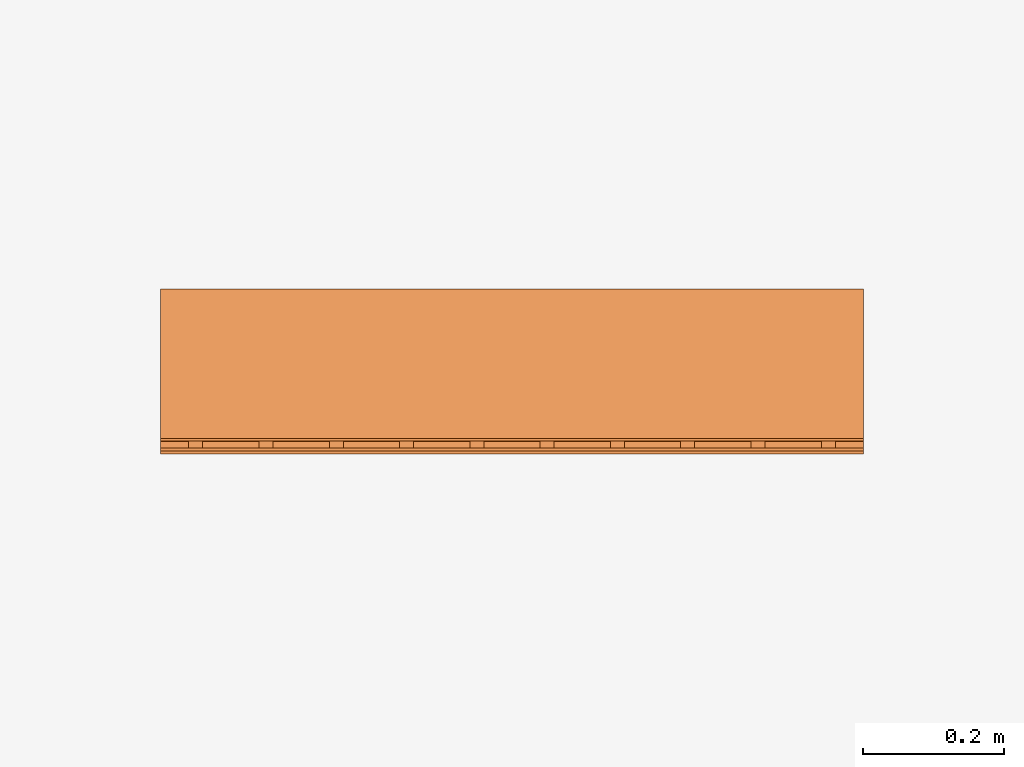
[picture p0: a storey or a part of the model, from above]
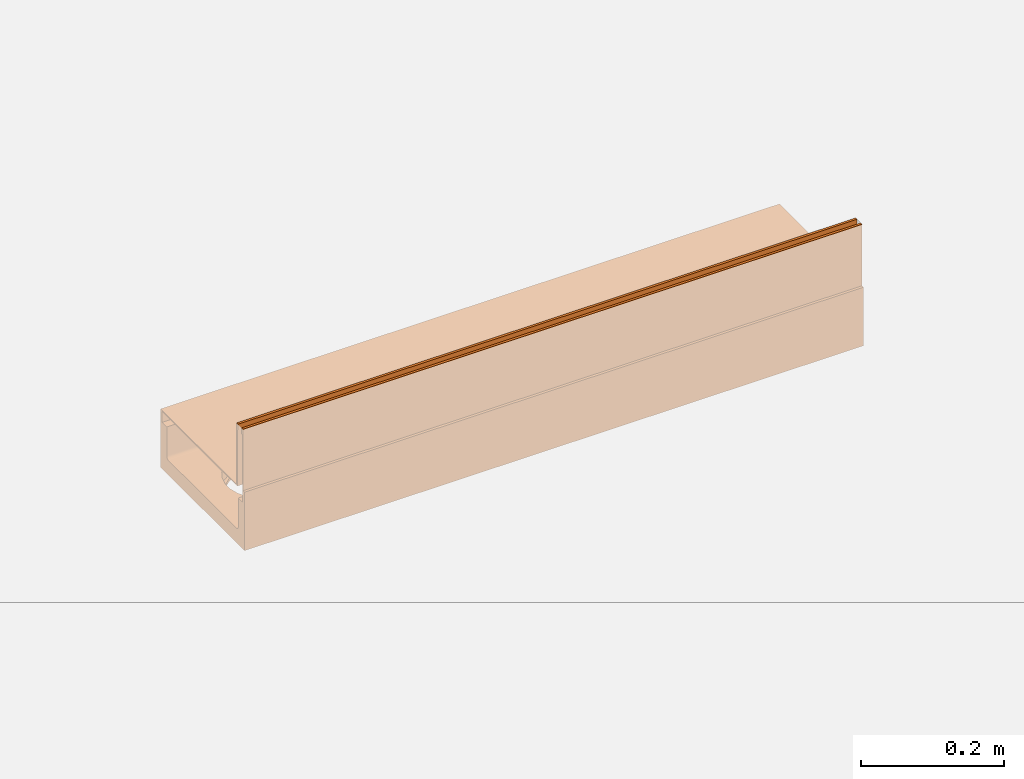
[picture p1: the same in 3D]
Properties of the parts of a building model (IFC2X3)

# File
Description: ViewDefinition [CoordinationView]
File name: 23217 - No 0100V Constant Depth Channel - 1000mm LG - Invert Depth 75mm.ifc
Time: 2013-10-30T13:49:25
Written by: Autodesk Revit 2013
Made in: 20120221_2030(x64)

# IfcProject, Project Number
LongName: Project Name; Phase: Project Status

# IfcSite, Default
RefLatitude: 42, 21, 30, 344238; RefLongitude: -71, -3, -35, -194702; RefElevation: 0 mm

# IfcBuilding
Pset_BuildingCommon - NumberOfStoreys: 1
Other - Project Address: ## Street City, State Zip; Project Name: Project Name; Client Name: Owner; Project Status: Project Status; Project Issue Date: Issue Date; Project Number: Project Number

# IfcBuildingStorey, Level 1
LongName: Level 1; Elevation: 0 mm
Constraints - Elevation Base: 0; Elevation: 0 mm
Graphics - Symbol at End 2 Default: yes; Line Weight: 1; Line Pattern: Center; Color: 0; Symbol: M_Level Head - Circle: M_Level Head - Circle; Symbol at End 1 Default: no
Dimensions - Computation Height: 0 mm
Identity Data - Building Story: yes; Name: Level 1; Structural: no

# IfcBuildingElementProxy: 23217 - No 0100V Constant Depth Channel - 1000mm LG - Invert Depth 75mm, Civil-Drainage-Channel-ACO-MultiDrain-M200D-Brickslot-Channel-System:23217 - No 0100V Constant Depth Channel - 1000mm LG - Invert Depth 75mm:23217 - No 0100V Constant Depth Channel - 1000mm LG - Invert Depth 75mm:196059
In: Level 1
Material: Steel, Galvanized, Plastic, Opaque Black, Vienite® Synthetic Resin Concrete
Model Properties - Brickslot Grating Product code 408996: Load Class C250/D400 - Brickslot Galvanized Steel - 500mm long x 105mm high - 10mm Slot - Intake area - 10000mm²/m - 4.8kg; End Cap Product code 23219: No. 306 Universal End Cap - 235mm wide x 365mm long - Spigot Ø160mm x 75mm long - Silver - Polypropylene - 0.4kg; Brickslot Grating Product code 408995: Load Class C250/D400 - Brickslot Galvanized Steel - 1000mm long x 105mm high - 10mm Slot - Intake area - 10000mm²/m - 9.8kg; Brickslot Access Unit Product code 408997: Load Class C250/D400 - Brickslot Access Unit Galvanised Steel - 500mm long x 105mm high - 10mm Slot - Intake area - 10000mm²/m 8.5 Kg
Dimensions - Brickslot Access Void Depth: -6000 mm; Brickslot Grating Void Depth: 0 mm; Brickslot Access Unit Void Bottom Depth: -6105 mm; EndCap Position: 1000 mm; Brickslot Void Length: -1000 mm; FloorCut_Length: -1000 mm; Custom_Void_Length: 0 mm; Volume: 8970757 mm3; Length: 1000 mm; InvDepth: 240 mm; Length Drain: -1000 mm; FloorCut_HorPosition: 117.5 mm; FloorCut_Width: 235 mm; EndCap_Height: 100 mm; FloorCut_Depth: 100 mm; Depth: 365 mm; Brickslot Access unit void length: -500 mm
Phasing - Phase Created: New Construction
Constraints - Level: Level: Level 1; Moves With Nearby Elements: no
Construction - 408995_Load Class C250 & D400_Brickslot Grating_Galvanized Steel_1000mm Long: yes; 23219 - Universal Endcap (Female End): no; 23219 - Universal Endcap (Male End): no; 408996_Load Class C250 & D400_Brickslot Grating_Galvanized Steel_500mm Long: no; 408997_Load Class C250 & D400_Brickslot_Access Unit_Galvanized Steel_500mm Long: no; Shallow Depth Channel: no; 23410_Sump Unit: no; Shallow Depth Channel with seal: yes; Constant Depth Channel_1000: no; Constant Depth Channel_500: no
Pset_BuildingElementProxyCommon - Reference: 23217 - No 0100V Constant Depth Channel - 1000mm LG - Invert Depth 75mm
Data - Invert Depth: 75mm; Concrete Surround Volume - Load Class A 15 - Concrete Pavement: 0.06m³/m; Concrete Surround Volume - Load Class D 400 - Concrete Pavement: 0.17m³/m; Pre-formed Outlet Ø: N/A; ACO Hydraulic Design Software: http://www.acodesign.co.uk; Installation - Concrete Grade: Refer to brochure; Hydraulic Performance: http://www.aco.co.uk/download.php?id=173; Product Weight: 17.0Kg; Product Dimensions: 1000mm x 235mm x 100mm (LxWxH); Load Class: A 15 - D 400; Channel C.S.A: 0.01m²; Concrete Surround Volume - Load Class B 125 - C 250 - Concrete Pavement: 0.11m³/m; Product Standard: BS EN 1433:2002, CE marked
Identity Data - Model Description: Channel drainage system; Maintenance guidelines: http://www.aco.co.uk/download.php?id=173; OmniClass Title: Rainwater Removal; Watermarked By: www.aco.co.uk; Installation guidelines: http://www.aco.co.uk/download.php?id=173; Product brochure: http://www.aco.co.uk/download.php?id=173; Cost: 0; Model: ACO MultiDrain MD Brickslot - M200D; OmniClass Number: 23.70.50.24; Watermark 2: This file is water marked and users are prohibited to reproduce, adapt, distribute this information; Product Page URL: http://www.aco.co.uk/product_detail.php?id=58; Telephone: +44 (0)1462 816666; Assembly Code: D2040; Fax: +44 (0)1462 815895; Type Comments: ACO MultiDrain M200D 0100V Shallow Constant Depth Channel 1000mm Long; Assembly Description: Rain Water Drainage; Product Code: 23217; Watermark 1: This file is the property of ACO Technologies PLC; Watermarked With: BIM Manager Premium Suite; e-mail Sales: customersupport@aco.co.uk; URL: www.aco.co.uk; e-mail Technical: technical@aco.co.uk; Address: ACO Business Park, Hitchin Road, Shefford, Bedfordshire, United Kingdom SG17 5TE; Price: POA - contact ACO; Manufacturer: ACO Technologies plc - ACO Water Management Division
General - SerialNumber: 0; TagNumber: 0
Materials and Finishes - Edge Rail Colour: Silver; Edge Rail Material: Steel; Channel Colour: Brown; Edge Rail Finish: Pre-galvanised; Channel Material: Vienite® Synthetic Resin Concrete
Green Building Properties - Channel Recyclable: Fully recyclable; Channel Recycled Material Content: 20% minimum; Edge Rail Recycled Material Content: Between 40% - 90%; Edge Rail Recyclable: Fully recyclable
Other - CreatedBy: www.aco.co.uk; Revision: 1

# IfcOpeningElement: Opening, Civil-Drainage-Channel-ACO-MultiDrain-M200D-Brickslot-Channel-System:23217 - No 0100V Constant Depth Channel - 1000mm LG - Invert Depth 75mm:23217 - No 0100V Constant Depth Channel - 1000mm LG - Invert Depth 75mm:196059:1
In: Level 1
Model Properties - Brickslot Grating Product code 408996: Load Class C250/D400 - Brickslot Galvanized Steel - 500mm long x 105mm high - 10mm Slot - Intake area - 10000mm²/m - 4.8kg; End Cap Product code 23219: No. 306 Universal End Cap - 235mm wide x 365mm long - Spigot Ø160mm x 75mm long - Silver - Polypropylene - 0.4kg; Brickslot Grating Product code 408995: Load Class C250/D400 - Brickslot Galvanized Steel - 1000mm long x 105mm high - 10mm Slot - Intake area - 10000mm²/m - 9.8kg; Brickslot Access Unit Product code 408997: Load Class C250/D400 - Brickslot Access Unit Galvanised Steel - 500mm long x 105mm high - 10mm Slot - Intake area - 10000mm²/m 8.5 Kg
Dimensions - Brickslot Access Void Depth: -6000 mm; Brickslot Grating Void Depth: 0 mm; Brickslot Access Unit Void Bottom Depth: -6105 mm; EndCap Position: 1000 mm; Brickslot Void Length: -1000 mm; FloorCut_Length: -1000 mm; Custom_Void_Length: 0 mm; Volume: 8970757 mm3; Length: 1000 mm; InvDepth: 240 mm; Length Drain: -1000 mm; FloorCut_HorPosition: 117.5 mm; FloorCut_Width: 235 mm; EndCap_Height: 100 mm; FloorCut_Depth: 100 mm; Depth: 365 mm; Brickslot Access unit void length: -500 mm
Phasing - Phase Created: New Construction
Constraints - Level: Level: Level 1; Moves With Nearby Elements: no
Construction - 408995_Load Class C250 & D400_Brickslot Grating_Galvanized Steel_1000mm Long: yes; 23219 - Universal Endcap (Female End): no; 23219 - Universal Endcap (Male End): no; 408996_Load Class C250 & D400_Brickslot Grating_Galvanized Steel_500mm Long: no; 408997_Load Class C250 & D400_Brickslot_Access Unit_Galvanized Steel_500mm Long: no; Shallow Depth Channel: no; 23410_Sump Unit: no; Shallow Depth Channel with seal: yes; Constant Depth Channel_1000: no; Constant Depth Channel_500: no
Data - Invert Depth: 75mm; Concrete Surround Volume - Load Class A 15 - Concrete Pavement: 0.06m³/m; Concrete Surround Volume - Load Class D 400 - Concrete Pavement: 0.17m³/m; Pre-formed Outlet Ø: N/A; ACO Hydraulic Design Software: http://www.acodesign.co.uk; Installation - Concrete Grade: Refer to brochure; Hydraulic Performance: http://www.aco.co.uk/download.php?id=173; Product Weight: 17.0Kg; Product Dimensions: 1000mm x 235mm x 100mm (LxWxH); Load Class: A 15 - D 400; Channel C.S.A: 0.01m²; Concrete Surround Volume - Load Class B 125 - C 250 - Concrete Pavement: 0.11m³/m; Product Standard: BS EN 1433:2002, CE marked
Identity Data - Model Description: Channel drainage system; Maintenance guidelines: http://www.aco.co.uk/download.php?id=173; OmniClass Title: Rainwater Removal; Watermarked By: www.aco.co.uk; Installation guidelines: http://www.aco.co.uk/download.php?id=173; Product brochure: http://www.aco.co.uk/download.php?id=173; Cost: 0; Model: ACO MultiDrain MD Brickslot - M200D; OmniClass Number: 23.70.50.24; Watermark 2: This file is water marked and users are prohibited to reproduce, adapt, distribute this information; Product Page URL: http://www.aco.co.uk/product_detail.php?id=58; Telephone: +44 (0)1462 816666; Assembly Code: D2040; Fax: +44 (0)1462 815895; Type Comments: ACO MultiDrain M200D 0100V Shallow Constant Depth Channel 1000mm Long; Assembly Description: Rain Water Drainage; Product Code: 23217; Watermark 1: This file is the property of ACO Technologies PLC; Watermarked With: BIM Manager Premium Suite; e-mail Sales: customersupport@aco.co.uk; URL: www.aco.co.uk; e-mail Technical: technical@aco.co.uk; Address: ACO Business Park, Hitchin Road, Shefford, Bedfordshire, United Kingdom SG17 5TE; Price: POA - contact ACO; Manufacturer: ACO Technologies plc - ACO Water Management Division
General - SerialNumber: 0; TagNumber: 0
Materials and Finishes - Edge Rail Colour: Silver; Edge Rail Material: Steel; Channel Colour: Brown; Edge Rail Finish: Pre-galvanised; Channel Material: Vienite® Synthetic Resin Concrete
Green Building Properties - Channel Recyclable: Fully recyclable; Channel Recycled Material Content: 20% minimum; Edge Rail Recycled Material Content: Between 40% - 90%; Edge Rail Recyclable: Fully recyclable
Other - CreatedBy: www.aco.co.uk; Revision: 1

# IfcOpeningElement: Recess (2)
In: Level 1
Dimensions - Perimeter: 20000 mm; Thickness: 400 mm; Area: 25000000 mm2; Volume: 9974610000 mm3
Constraints - Level: Level: Level 1; Room Bounding: yes; Related to Mass: no; Height Offset From Level: 0 mm
Phasing - Phase Created: New Construction
Structural - Structural: no; Enable Analytical Model: no
Analytical Properties - Absorptance: 0.1; Roughness: 1; Heat Transfer Coefficient (U): 2.0925; Thermal Resistance (R): 0.477897; Thermal mass: 543920
Graphics - Coarse Scale Fill Color: 0
Materials and Finishes - Structural Material: Earth
Construction - Default Thickness: 400 mm; Function: 0

# IfcSlab: Floor:Generic Floor - 400mm, Floor:Generic Floor - 400mm:193825
In: Level 1
PredefinedType: FLOOR; Material: Earth 400 mm
Dimensions - Perimeter: 20000 mm; Thickness: 400 mm; Area: 25000000 mm2; Volume: 9974610000 mm3
Constraints - Level: Level: Level 1; Room Bounding: yes; Related to Mass: no; Height Offset From Level: 0 mm
Phasing - Phase Created: New Construction
Structural - Structural: no; Enable Analytical Model: no
Pset_SlabCommon - Reference: Generic Floor - 400mm; IsExternal: no; LoadBearing: yes
Analytical Properties - Absorptance: 0.1; Roughness: 1; Heat Transfer Coefficient (U): 2.0925; Thermal Resistance (R): 0.477897; Thermal mass: 543920
Graphics - Coarse Scale Fill Color: 0
Materials and Finishes - Structural Material: Earth
Construction - Default Thickness: 400 mm; Function: 0
